VERSION 5.7 ;
BUSBITCHARS "[]" ;
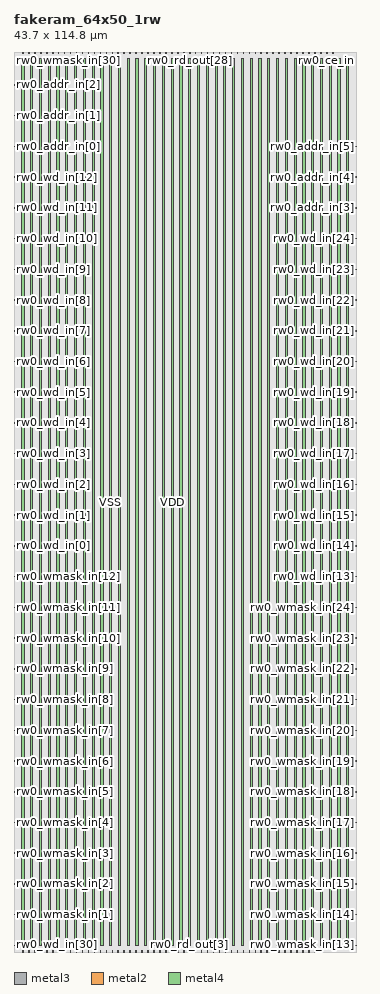
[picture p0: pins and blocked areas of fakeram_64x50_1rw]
MACRO fakeram_64x50_1rw
  FOREIGN fakeram_64x50_1rw 0 0 ;
  SYMMETRY X Y R90 ;
  SIZE 43.700 BY 114.800 ;
  CLASS BLOCK ;
  PIN rw0_wmask_in[0]
    DIRECTION INPUT ;
    USE SIGNAL ;
    SHAPE ABUTMENT ;
    PORT
      LAYER metal3 ;
      RECT 0.000 0.805 0.210 0.875 ;
    END
  END rw0_wmask_in[0]
  PIN rw0_wmask_in[1]
    DIRECTION INPUT ;
    USE SIGNAL ;
    SHAPE ABUTMENT ;
    PORT
      LAYER metal3 ;
      RECT 0.000 4.725 0.210 4.795 ;
    END
  END rw0_wmask_in[1]
  PIN rw0_wmask_in[2]
    DIRECTION INPUT ;
    USE SIGNAL ;
    SHAPE ABUTMENT ;
    PORT
      LAYER metal3 ;
      RECT 0.000 8.645 0.210 8.715 ;
    END
  END rw0_wmask_in[2]
  PIN rw0_wmask_in[3]
    DIRECTION INPUT ;
    USE SIGNAL ;
    SHAPE ABUTMENT ;
    PORT
      LAYER metal3 ;
      RECT 0.000 12.565 0.210 12.635 ;
    END
  END rw0_wmask_in[3]
  PIN rw0_wmask_in[4]
    DIRECTION INPUT ;
    USE SIGNAL ;
    SHAPE ABUTMENT ;
    PORT
      LAYER metal3 ;
      RECT 0.000 16.485 0.210 16.555 ;
    END
  END rw0_wmask_in[4]
  PIN rw0_wmask_in[5]
    DIRECTION INPUT ;
    USE SIGNAL ;
    SHAPE ABUTMENT ;
    PORT
      LAYER metal3 ;
      RECT 0.000 20.405 0.210 20.475 ;
    END
  END rw0_wmask_in[5]
  PIN rw0_wmask_in[6]
    DIRECTION INPUT ;
    USE SIGNAL ;
    SHAPE ABUTMENT ;
    PORT
      LAYER metal3 ;
      RECT 0.000 24.325 0.210 24.395 ;
    END
  END rw0_wmask_in[6]
  PIN rw0_wmask_in[7]
    DIRECTION INPUT ;
    USE SIGNAL ;
    SHAPE ABUTMENT ;
    PORT
      LAYER metal3 ;
      RECT 0.000 28.245 0.210 28.315 ;
    END
  END rw0_wmask_in[7]
  PIN rw0_wmask_in[8]
    DIRECTION INPUT ;
    USE SIGNAL ;
    SHAPE ABUTMENT ;
    PORT
      LAYER metal3 ;
      RECT 0.000 32.165 0.210 32.235 ;
    END
  END rw0_wmask_in[8]
  PIN rw0_wmask_in[9]
    DIRECTION INPUT ;
    USE SIGNAL ;
    SHAPE ABUTMENT ;
    PORT
      LAYER metal3 ;
      RECT 0.000 36.085 0.210 36.155 ;
    END
  END rw0_wmask_in[9]
  PIN rw0_wmask_in[10]
    DIRECTION INPUT ;
    USE SIGNAL ;
    SHAPE ABUTMENT ;
    PORT
      LAYER metal3 ;
      RECT 0.000 40.005 0.210 40.075 ;
    END
  END rw0_wmask_in[10]
  PIN rw0_wmask_in[11]
    DIRECTION INPUT ;
    USE SIGNAL ;
    SHAPE ABUTMENT ;
    PORT
      LAYER metal3 ;
      RECT 0.000 43.925 0.210 43.995 ;
    END
  END rw0_wmask_in[11]
  PIN rw0_wmask_in[12]
    DIRECTION INPUT ;
    USE SIGNAL ;
    SHAPE ABUTMENT ;
    PORT
      LAYER metal3 ;
      RECT 0.000 47.845 0.210 47.915 ;
    END
  END rw0_wmask_in[12]
  PIN rw0_wmask_in[13]
    DIRECTION INPUT ;
    USE SIGNAL ;
    SHAPE ABUTMENT ;
    PORT
      LAYER metal3 ;
      RECT 43.490 0.805 43.700 0.875 ;
    END
  END rw0_wmask_in[13]
  PIN rw0_wmask_in[14]
    DIRECTION INPUT ;
    USE SIGNAL ;
    SHAPE ABUTMENT ;
    PORT
      LAYER metal3 ;
      RECT 43.490 4.725 43.700 4.795 ;
    END
  END rw0_wmask_in[14]
  PIN rw0_wmask_in[15]
    DIRECTION INPUT ;
    USE SIGNAL ;
    SHAPE ABUTMENT ;
    PORT
      LAYER metal3 ;
      RECT 43.490 8.645 43.700 8.715 ;
    END
  END rw0_wmask_in[15]
  PIN rw0_wmask_in[16]
    DIRECTION INPUT ;
    USE SIGNAL ;
    SHAPE ABUTMENT ;
    PORT
      LAYER metal3 ;
      RECT 43.490 12.565 43.700 12.635 ;
    END
  END rw0_wmask_in[16]
  PIN rw0_wmask_in[17]
    DIRECTION INPUT ;
    USE SIGNAL ;
    SHAPE ABUTMENT ;
    PORT
      LAYER metal3 ;
      RECT 43.490 16.485 43.700 16.555 ;
    END
  END rw0_wmask_in[17]
  PIN rw0_wmask_in[18]
    DIRECTION INPUT ;
    USE SIGNAL ;
    SHAPE ABUTMENT ;
    PORT
      LAYER metal3 ;
      RECT 43.490 20.405 43.700 20.475 ;
    END
  END rw0_wmask_in[18]
  PIN rw0_wmask_in[19]
    DIRECTION INPUT ;
    USE SIGNAL ;
    SHAPE ABUTMENT ;
    PORT
      LAYER metal3 ;
      RECT 43.490 24.325 43.700 24.395 ;
    END
  END rw0_wmask_in[19]
  PIN rw0_wmask_in[20]
    DIRECTION INPUT ;
    USE SIGNAL ;
    SHAPE ABUTMENT ;
    PORT
      LAYER metal3 ;
      RECT 43.490 28.245 43.700 28.315 ;
    END
  END rw0_wmask_in[20]
  PIN rw0_wmask_in[21]
    DIRECTION INPUT ;
    USE SIGNAL ;
    SHAPE ABUTMENT ;
    PORT
      LAYER metal3 ;
      RECT 43.490 32.165 43.700 32.235 ;
    END
  END rw0_wmask_in[21]
  PIN rw0_wmask_in[22]
    DIRECTION INPUT ;
    USE SIGNAL ;
    SHAPE ABUTMENT ;
    PORT
      LAYER metal3 ;
      RECT 43.490 36.085 43.700 36.155 ;
    END
  END rw0_wmask_in[22]
  PIN rw0_wmask_in[23]
    DIRECTION INPUT ;
    USE SIGNAL ;
    SHAPE ABUTMENT ;
    PORT
      LAYER metal3 ;
      RECT 43.490 40.005 43.700 40.075 ;
    END
  END rw0_wmask_in[23]
  PIN rw0_wmask_in[24]
    DIRECTION INPUT ;
    USE SIGNAL ;
    SHAPE ABUTMENT ;
    PORT
      LAYER metal3 ;
      RECT 43.490 43.925 43.700 43.995 ;
    END
  END rw0_wmask_in[24]
  PIN rw0_wmask_in[25]
    DIRECTION INPUT ;
    USE SIGNAL ;
    SHAPE ABUTMENT ;
    PORT
      LAYER metal2 ;
      RECT 1.105 114.590 1.175 114.800 ;
    END
  END rw0_wmask_in[25]
  PIN rw0_wmask_in[26]
    DIRECTION INPUT ;
    USE SIGNAL ;
    SHAPE ABUTMENT ;
    PORT
      LAYER metal2 ;
      RECT 1.865 114.590 1.935 114.800 ;
    END
  END rw0_wmask_in[26]
  PIN rw0_wmask_in[27]
    DIRECTION INPUT ;
    USE SIGNAL ;
    SHAPE ABUTMENT ;
    PORT
      LAYER metal2 ;
      RECT 2.625 114.590 2.695 114.800 ;
    END
  END rw0_wmask_in[27]
  PIN rw0_wmask_in[28]
    DIRECTION INPUT ;
    USE SIGNAL ;
    SHAPE ABUTMENT ;
    PORT
      LAYER metal2 ;
      RECT 3.385 114.590 3.455 114.800 ;
    END
  END rw0_wmask_in[28]
  PIN rw0_wmask_in[29]
    DIRECTION INPUT ;
    USE SIGNAL ;
    SHAPE ABUTMENT ;
    PORT
      LAYER metal2 ;
      RECT 4.145 114.590 4.215 114.800 ;
    END
  END rw0_wmask_in[29]
  PIN rw0_wmask_in[30]
    DIRECTION INPUT ;
    USE SIGNAL ;
    SHAPE ABUTMENT ;
    PORT
      LAYER metal2 ;
      RECT 4.905 114.590 4.975 114.800 ;
    END
  END rw0_wmask_in[30]
  PIN rw0_wmask_in[31]
    DIRECTION INPUT ;
    USE SIGNAL ;
    SHAPE ABUTMENT ;
    PORT
      LAYER metal2 ;
      RECT 5.665 114.590 5.735 114.800 ;
    END
  END rw0_wmask_in[31]
  PIN rw0_wmask_in[32]
    DIRECTION INPUT ;
    USE SIGNAL ;
    SHAPE ABUTMENT ;
    PORT
      LAYER metal2 ;
      RECT 6.425 114.590 6.495 114.800 ;
    END
  END rw0_wmask_in[32]
  PIN rw0_wmask_in[33]
    DIRECTION INPUT ;
    USE SIGNAL ;
    SHAPE ABUTMENT ;
    PORT
      LAYER metal2 ;
      RECT 7.185 114.590 7.255 114.800 ;
    END
  END rw0_wmask_in[33]
  PIN rw0_wmask_in[34]
    DIRECTION INPUT ;
    USE SIGNAL ;
    SHAPE ABUTMENT ;
    PORT
      LAYER metal2 ;
      RECT 7.945 114.590 8.015 114.800 ;
    END
  END rw0_wmask_in[34]
  PIN rw0_wmask_in[35]
    DIRECTION INPUT ;
    USE SIGNAL ;
    SHAPE ABUTMENT ;
    PORT
      LAYER metal2 ;
      RECT 8.705 114.590 8.775 114.800 ;
    END
  END rw0_wmask_in[35]
  PIN rw0_wmask_in[36]
    DIRECTION INPUT ;
    USE SIGNAL ;
    SHAPE ABUTMENT ;
    PORT
      LAYER metal2 ;
      RECT 9.465 114.590 9.535 114.800 ;
    END
  END rw0_wmask_in[36]
  PIN rw0_wmask_in[37]
    DIRECTION INPUT ;
    USE SIGNAL ;
    SHAPE ABUTMENT ;
    PORT
      LAYER metal2 ;
      RECT 10.225 114.590 10.295 114.800 ;
    END
  END rw0_wmask_in[37]
  PIN rw0_wmask_in[38]
    DIRECTION INPUT ;
    USE SIGNAL ;
    SHAPE ABUTMENT ;
    PORT
      LAYER metal2 ;
      RECT 10.985 114.590 11.055 114.800 ;
    END
  END rw0_wmask_in[38]
  PIN rw0_wmask_in[39]
    DIRECTION INPUT ;
    USE SIGNAL ;
    SHAPE ABUTMENT ;
    PORT
      LAYER metal2 ;
      RECT 11.745 114.590 11.815 114.800 ;
    END
  END rw0_wmask_in[39]
  PIN rw0_wmask_in[40]
    DIRECTION INPUT ;
    USE SIGNAL ;
    SHAPE ABUTMENT ;
    PORT
      LAYER metal2 ;
      RECT 12.505 114.590 12.575 114.800 ;
    END
  END rw0_wmask_in[40]
  PIN rw0_wmask_in[41]
    DIRECTION INPUT ;
    USE SIGNAL ;
    SHAPE ABUTMENT ;
    PORT
      LAYER metal2 ;
      RECT 13.265 114.590 13.335 114.800 ;
    END
  END rw0_wmask_in[41]
  PIN rw0_wmask_in[42]
    DIRECTION INPUT ;
    USE SIGNAL ;
    SHAPE ABUTMENT ;
    PORT
      LAYER metal2 ;
      RECT 14.025 114.590 14.095 114.800 ;
    END
  END rw0_wmask_in[42]
  PIN rw0_wmask_in[43]
    DIRECTION INPUT ;
    USE SIGNAL ;
    SHAPE ABUTMENT ;
    PORT
      LAYER metal2 ;
      RECT 14.785 114.590 14.855 114.800 ;
    END
  END rw0_wmask_in[43]
  PIN rw0_wmask_in[44]
    DIRECTION INPUT ;
    USE SIGNAL ;
    SHAPE ABUTMENT ;
    PORT
      LAYER metal2 ;
      RECT 15.545 114.590 15.615 114.800 ;
    END
  END rw0_wmask_in[44]
  PIN rw0_wmask_in[45]
    DIRECTION INPUT ;
    USE SIGNAL ;
    SHAPE ABUTMENT ;
    PORT
      LAYER metal2 ;
      RECT 16.305 114.590 16.375 114.800 ;
    END
  END rw0_wmask_in[45]
  PIN rw0_wmask_in[46]
    DIRECTION INPUT ;
    USE SIGNAL ;
    SHAPE ABUTMENT ;
    PORT
      LAYER metal2 ;
      RECT 17.065 114.590 17.135 114.800 ;
    END
  END rw0_wmask_in[46]
  PIN rw0_wmask_in[47]
    DIRECTION INPUT ;
    USE SIGNAL ;
    SHAPE ABUTMENT ;
    PORT
      LAYER metal2 ;
      RECT 17.825 114.590 17.895 114.800 ;
    END
  END rw0_wmask_in[47]
  PIN rw0_wmask_in[48]
    DIRECTION INPUT ;
    USE SIGNAL ;
    SHAPE ABUTMENT ;
    PORT
      LAYER metal2 ;
      RECT 18.585 114.590 18.655 114.800 ;
    END
  END rw0_wmask_in[48]
  PIN rw0_wmask_in[49]
    DIRECTION INPUT ;
    USE SIGNAL ;
    SHAPE ABUTMENT ;
    PORT
      LAYER metal2 ;
      RECT 19.345 114.590 19.415 114.800 ;
    END
  END rw0_wmask_in[49]
  PIN rw0_wd_in[0]
    DIRECTION INPUT ;
    USE SIGNAL ;
    SHAPE ABUTMENT ;
    PORT
      LAYER metal3 ;
      RECT 0.000 51.765 0.210 51.835 ;
    END
  END rw0_wd_in[0]
  PIN rw0_wd_in[1]
    DIRECTION INPUT ;
    USE SIGNAL ;
    SHAPE ABUTMENT ;
    PORT
      LAYER metal3 ;
      RECT 0.000 55.685 0.210 55.755 ;
    END
  END rw0_wd_in[1]
  PIN rw0_wd_in[2]
    DIRECTION INPUT ;
    USE SIGNAL ;
    SHAPE ABUTMENT ;
    PORT
      LAYER metal3 ;
      RECT 0.000 59.605 0.210 59.675 ;
    END
  END rw0_wd_in[2]
  PIN rw0_wd_in[3]
    DIRECTION INPUT ;
    USE SIGNAL ;
    SHAPE ABUTMENT ;
    PORT
      LAYER metal3 ;
      RECT 0.000 63.525 0.210 63.595 ;
    END
  END rw0_wd_in[3]
  PIN rw0_wd_in[4]
    DIRECTION INPUT ;
    USE SIGNAL ;
    SHAPE ABUTMENT ;
    PORT
      LAYER metal3 ;
      RECT 0.000 67.445 0.210 67.515 ;
    END
  END rw0_wd_in[4]
  PIN rw0_wd_in[5]
    DIRECTION INPUT ;
    USE SIGNAL ;
    SHAPE ABUTMENT ;
    PORT
      LAYER metal3 ;
      RECT 0.000 71.365 0.210 71.435 ;
    END
  END rw0_wd_in[5]
  PIN rw0_wd_in[6]
    DIRECTION INPUT ;
    USE SIGNAL ;
    SHAPE ABUTMENT ;
    PORT
      LAYER metal3 ;
      RECT 0.000 75.285 0.210 75.355 ;
    END
  END rw0_wd_in[6]
  PIN rw0_wd_in[7]
    DIRECTION INPUT ;
    USE SIGNAL ;
    SHAPE ABUTMENT ;
    PORT
      LAYER metal3 ;
      RECT 0.000 79.205 0.210 79.275 ;
    END
  END rw0_wd_in[7]
  PIN rw0_wd_in[8]
    DIRECTION INPUT ;
    USE SIGNAL ;
    SHAPE ABUTMENT ;
    PORT
      LAYER metal3 ;
      RECT 0.000 83.125 0.210 83.195 ;
    END
  END rw0_wd_in[8]
  PIN rw0_wd_in[9]
    DIRECTION INPUT ;
    USE SIGNAL ;
    SHAPE ABUTMENT ;
    PORT
      LAYER metal3 ;
      RECT 0.000 87.045 0.210 87.115 ;
    END
  END rw0_wd_in[9]
  PIN rw0_wd_in[10]
    DIRECTION INPUT ;
    USE SIGNAL ;
    SHAPE ABUTMENT ;
    PORT
      LAYER metal3 ;
      RECT 0.000 90.965 0.210 91.035 ;
    END
  END rw0_wd_in[10]
  PIN rw0_wd_in[11]
    DIRECTION INPUT ;
    USE SIGNAL ;
    SHAPE ABUTMENT ;
    PORT
      LAYER metal3 ;
      RECT 0.000 94.885 0.210 94.955 ;
    END
  END rw0_wd_in[11]
  PIN rw0_wd_in[12]
    DIRECTION INPUT ;
    USE SIGNAL ;
    SHAPE ABUTMENT ;
    PORT
      LAYER metal3 ;
      RECT 0.000 98.805 0.210 98.875 ;
    END
  END rw0_wd_in[12]
  PIN rw0_wd_in[13]
    DIRECTION INPUT ;
    USE SIGNAL ;
    SHAPE ABUTMENT ;
    PORT
      LAYER metal3 ;
      RECT 43.490 47.845 43.700 47.915 ;
    END
  END rw0_wd_in[13]
  PIN rw0_wd_in[14]
    DIRECTION INPUT ;
    USE SIGNAL ;
    SHAPE ABUTMENT ;
    PORT
      LAYER metal3 ;
      RECT 43.490 51.765 43.700 51.835 ;
    END
  END rw0_wd_in[14]
  PIN rw0_wd_in[15]
    DIRECTION INPUT ;
    USE SIGNAL ;
    SHAPE ABUTMENT ;
    PORT
      LAYER metal3 ;
      RECT 43.490 55.685 43.700 55.755 ;
    END
  END rw0_wd_in[15]
  PIN rw0_wd_in[16]
    DIRECTION INPUT ;
    USE SIGNAL ;
    SHAPE ABUTMENT ;
    PORT
      LAYER metal3 ;
      RECT 43.490 59.605 43.700 59.675 ;
    END
  END rw0_wd_in[16]
  PIN rw0_wd_in[17]
    DIRECTION INPUT ;
    USE SIGNAL ;
    SHAPE ABUTMENT ;
    PORT
      LAYER metal3 ;
      RECT 43.490 63.525 43.700 63.595 ;
    END
  END rw0_wd_in[17]
  PIN rw0_wd_in[18]
    DIRECTION INPUT ;
    USE SIGNAL ;
    SHAPE ABUTMENT ;
    PORT
      LAYER metal3 ;
      RECT 43.490 67.445 43.700 67.515 ;
    END
  END rw0_wd_in[18]
  PIN rw0_wd_in[19]
    DIRECTION INPUT ;
    USE SIGNAL ;
    SHAPE ABUTMENT ;
    PORT
      LAYER metal3 ;
      RECT 43.490 71.365 43.700 71.435 ;
    END
  END rw0_wd_in[19]
  PIN rw0_wd_in[20]
    DIRECTION INPUT ;
    USE SIGNAL ;
    SHAPE ABUTMENT ;
    PORT
      LAYER metal3 ;
      RECT 43.490 75.285 43.700 75.355 ;
    END
  END rw0_wd_in[20]
  PIN rw0_wd_in[21]
    DIRECTION INPUT ;
    USE SIGNAL ;
    SHAPE ABUTMENT ;
    PORT
      LAYER metal3 ;
      RECT 43.490 79.205 43.700 79.275 ;
    END
  END rw0_wd_in[21]
  PIN rw0_wd_in[22]
    DIRECTION INPUT ;
    USE SIGNAL ;
    SHAPE ABUTMENT ;
    PORT
      LAYER metal3 ;
      RECT 43.490 83.125 43.700 83.195 ;
    END
  END rw0_wd_in[22]
  PIN rw0_wd_in[23]
    DIRECTION INPUT ;
    USE SIGNAL ;
    SHAPE ABUTMENT ;
    PORT
      LAYER metal3 ;
      RECT 43.490 87.045 43.700 87.115 ;
    END
  END rw0_wd_in[23]
  PIN rw0_wd_in[24]
    DIRECTION INPUT ;
    USE SIGNAL ;
    SHAPE ABUTMENT ;
    PORT
      LAYER metal3 ;
      RECT 43.490 90.965 43.700 91.035 ;
    END
  END rw0_wd_in[24]
  PIN rw0_wd_in[25]
    DIRECTION INPUT ;
    USE SIGNAL ;
    SHAPE ABUTMENT ;
    PORT
      LAYER metal2 ;
      RECT 1.105 0.000 1.175 0.210 ;
    END
  END rw0_wd_in[25]
  PIN rw0_wd_in[26]
    DIRECTION INPUT ;
    USE SIGNAL ;
    SHAPE ABUTMENT ;
    PORT
      LAYER metal2 ;
      RECT 1.865 0.000 1.935 0.210 ;
    END
  END rw0_wd_in[26]
  PIN rw0_wd_in[27]
    DIRECTION INPUT ;
    USE SIGNAL ;
    SHAPE ABUTMENT ;
    PORT
      LAYER metal2 ;
      RECT 2.625 0.000 2.695 0.210 ;
    END
  END rw0_wd_in[27]
  PIN rw0_wd_in[28]
    DIRECTION INPUT ;
    USE SIGNAL ;
    SHAPE ABUTMENT ;
    PORT
      LAYER metal2 ;
      RECT 3.385 0.000 3.455 0.210 ;
    END
  END rw0_wd_in[28]
  PIN rw0_wd_in[29]
    DIRECTION INPUT ;
    USE SIGNAL ;
    SHAPE ABUTMENT ;
    PORT
      LAYER metal2 ;
      RECT 4.145 0.000 4.215 0.210 ;
    END
  END rw0_wd_in[29]
  PIN rw0_wd_in[30]
    DIRECTION INPUT ;
    USE SIGNAL ;
    SHAPE ABUTMENT ;
    PORT
      LAYER metal2 ;
      RECT 4.905 0.000 4.975 0.210 ;
    END
  END rw0_wd_in[30]
  PIN rw0_wd_in[31]
    DIRECTION INPUT ;
    USE SIGNAL ;
    SHAPE ABUTMENT ;
    PORT
      LAYER metal2 ;
      RECT 5.665 0.000 5.735 0.210 ;
    END
  END rw0_wd_in[31]
  PIN rw0_wd_in[32]
    DIRECTION INPUT ;
    USE SIGNAL ;
    SHAPE ABUTMENT ;
    PORT
      LAYER metal2 ;
      RECT 6.425 0.000 6.495 0.210 ;
    END
  END rw0_wd_in[32]
  PIN rw0_wd_in[33]
    DIRECTION INPUT ;
    USE SIGNAL ;
    SHAPE ABUTMENT ;
    PORT
      LAYER metal2 ;
      RECT 7.185 0.000 7.255 0.210 ;
    END
  END rw0_wd_in[33]
  PIN rw0_wd_in[34]
    DIRECTION INPUT ;
    USE SIGNAL ;
    SHAPE ABUTMENT ;
    PORT
      LAYER metal2 ;
      RECT 7.945 0.000 8.015 0.210 ;
    END
  END rw0_wd_in[34]
  PIN rw0_wd_in[35]
    DIRECTION INPUT ;
    USE SIGNAL ;
    SHAPE ABUTMENT ;
    PORT
      LAYER metal2 ;
      RECT 8.705 0.000 8.775 0.210 ;
    END
  END rw0_wd_in[35]
  PIN rw0_wd_in[36]
    DIRECTION INPUT ;
    USE SIGNAL ;
    SHAPE ABUTMENT ;
    PORT
      LAYER metal2 ;
      RECT 9.465 0.000 9.535 0.210 ;
    END
  END rw0_wd_in[36]
  PIN rw0_wd_in[37]
    DIRECTION INPUT ;
    USE SIGNAL ;
    SHAPE ABUTMENT ;
    PORT
      LAYER metal2 ;
      RECT 10.225 0.000 10.295 0.210 ;
    END
  END rw0_wd_in[37]
  PIN rw0_wd_in[38]
    DIRECTION INPUT ;
    USE SIGNAL ;
    SHAPE ABUTMENT ;
    PORT
      LAYER metal2 ;
      RECT 10.985 0.000 11.055 0.210 ;
    END
  END rw0_wd_in[38]
  PIN rw0_wd_in[39]
    DIRECTION INPUT ;
    USE SIGNAL ;
    SHAPE ABUTMENT ;
    PORT
      LAYER metal2 ;
      RECT 11.745 0.000 11.815 0.210 ;
    END
  END rw0_wd_in[39]
  PIN rw0_wd_in[40]
    DIRECTION INPUT ;
    USE SIGNAL ;
    SHAPE ABUTMENT ;
    PORT
      LAYER metal2 ;
      RECT 12.505 0.000 12.575 0.210 ;
    END
  END rw0_wd_in[40]
  PIN rw0_wd_in[41]
    DIRECTION INPUT ;
    USE SIGNAL ;
    SHAPE ABUTMENT ;
    PORT
      LAYER metal2 ;
      RECT 13.265 0.000 13.335 0.210 ;
    END
  END rw0_wd_in[41]
  PIN rw0_wd_in[42]
    DIRECTION INPUT ;
    USE SIGNAL ;
    SHAPE ABUTMENT ;
    PORT
      LAYER metal2 ;
      RECT 14.025 0.000 14.095 0.210 ;
    END
  END rw0_wd_in[42]
  PIN rw0_wd_in[43]
    DIRECTION INPUT ;
    USE SIGNAL ;
    SHAPE ABUTMENT ;
    PORT
      LAYER metal2 ;
      RECT 14.785 0.000 14.855 0.210 ;
    END
  END rw0_wd_in[43]
  PIN rw0_wd_in[44]
    DIRECTION INPUT ;
    USE SIGNAL ;
    SHAPE ABUTMENT ;
    PORT
      LAYER metal2 ;
      RECT 15.545 0.000 15.615 0.210 ;
    END
  END rw0_wd_in[44]
  PIN rw0_wd_in[45]
    DIRECTION INPUT ;
    USE SIGNAL ;
    SHAPE ABUTMENT ;
    PORT
      LAYER metal2 ;
      RECT 16.305 0.000 16.375 0.210 ;
    END
  END rw0_wd_in[45]
  PIN rw0_wd_in[46]
    DIRECTION INPUT ;
    USE SIGNAL ;
    SHAPE ABUTMENT ;
    PORT
      LAYER metal2 ;
      RECT 17.065 0.000 17.135 0.210 ;
    END
  END rw0_wd_in[46]
  PIN rw0_wd_in[47]
    DIRECTION INPUT ;
    USE SIGNAL ;
    SHAPE ABUTMENT ;
    PORT
      LAYER metal2 ;
      RECT 17.825 0.000 17.895 0.210 ;
    END
  END rw0_wd_in[47]
  PIN rw0_wd_in[48]
    DIRECTION INPUT ;
    USE SIGNAL ;
    SHAPE ABUTMENT ;
    PORT
      LAYER metal2 ;
      RECT 18.585 0.000 18.655 0.210 ;
    END
  END rw0_wd_in[48]
  PIN rw0_wd_in[49]
    DIRECTION INPUT ;
    USE SIGNAL ;
    SHAPE ABUTMENT ;
    PORT
      LAYER metal2 ;
      RECT 19.345 0.000 19.415 0.210 ;
    END
  END rw0_wd_in[49]
  PIN rw0_rd_out[0]
    DIRECTION OUTPUT ;
    USE SIGNAL ;
    SHAPE ABUTMENT ;
    PORT
      LAYER metal2 ;
      RECT 20.105 0.000 20.175 0.210 ;
    END
  END rw0_rd_out[0]
  PIN rw0_rd_out[1]
    DIRECTION OUTPUT ;
    USE SIGNAL ;
    SHAPE ABUTMENT ;
    PORT
      LAYER metal2 ;
      RECT 20.865 0.000 20.935 0.210 ;
    END
  END rw0_rd_out[1]
  PIN rw0_rd_out[2]
    DIRECTION OUTPUT ;
    USE SIGNAL ;
    SHAPE ABUTMENT ;
    PORT
      LAYER metal2 ;
      RECT 21.625 0.000 21.695 0.210 ;
    END
  END rw0_rd_out[2]
  PIN rw0_rd_out[3]
    DIRECTION OUTPUT ;
    USE SIGNAL ;
    SHAPE ABUTMENT ;
    PORT
      LAYER metal2 ;
      RECT 22.385 0.000 22.455 0.210 ;
    END
  END rw0_rd_out[3]
  PIN rw0_rd_out[4]
    DIRECTION OUTPUT ;
    USE SIGNAL ;
    SHAPE ABUTMENT ;
    PORT
      LAYER metal2 ;
      RECT 23.145 0.000 23.215 0.210 ;
    END
  END rw0_rd_out[4]
  PIN rw0_rd_out[5]
    DIRECTION OUTPUT ;
    USE SIGNAL ;
    SHAPE ABUTMENT ;
    PORT
      LAYER metal2 ;
      RECT 23.905 0.000 23.975 0.210 ;
    END
  END rw0_rd_out[5]
  PIN rw0_rd_out[6]
    DIRECTION OUTPUT ;
    USE SIGNAL ;
    SHAPE ABUTMENT ;
    PORT
      LAYER metal2 ;
      RECT 24.665 0.000 24.735 0.210 ;
    END
  END rw0_rd_out[6]
  PIN rw0_rd_out[7]
    DIRECTION OUTPUT ;
    USE SIGNAL ;
    SHAPE ABUTMENT ;
    PORT
      LAYER metal2 ;
      RECT 25.425 0.000 25.495 0.210 ;
    END
  END rw0_rd_out[7]
  PIN rw0_rd_out[8]
    DIRECTION OUTPUT ;
    USE SIGNAL ;
    SHAPE ABUTMENT ;
    PORT
      LAYER metal2 ;
      RECT 26.185 0.000 26.255 0.210 ;
    END
  END rw0_rd_out[8]
  PIN rw0_rd_out[9]
    DIRECTION OUTPUT ;
    USE SIGNAL ;
    SHAPE ABUTMENT ;
    PORT
      LAYER metal2 ;
      RECT 26.945 0.000 27.015 0.210 ;
    END
  END rw0_rd_out[9]
  PIN rw0_rd_out[10]
    DIRECTION OUTPUT ;
    USE SIGNAL ;
    SHAPE ABUTMENT ;
    PORT
      LAYER metal2 ;
      RECT 27.705 0.000 27.775 0.210 ;
    END
  END rw0_rd_out[10]
  PIN rw0_rd_out[11]
    DIRECTION OUTPUT ;
    USE SIGNAL ;
    SHAPE ABUTMENT ;
    PORT
      LAYER metal2 ;
      RECT 28.465 0.000 28.535 0.210 ;
    END
  END rw0_rd_out[11]
  PIN rw0_rd_out[12]
    DIRECTION OUTPUT ;
    USE SIGNAL ;
    SHAPE ABUTMENT ;
    PORT
      LAYER metal2 ;
      RECT 29.225 0.000 29.295 0.210 ;
    END
  END rw0_rd_out[12]
  PIN rw0_rd_out[13]
    DIRECTION OUTPUT ;
    USE SIGNAL ;
    SHAPE ABUTMENT ;
    PORT
      LAYER metal2 ;
      RECT 29.985 0.000 30.055 0.210 ;
    END
  END rw0_rd_out[13]
  PIN rw0_rd_out[14]
    DIRECTION OUTPUT ;
    USE SIGNAL ;
    SHAPE ABUTMENT ;
    PORT
      LAYER metal2 ;
      RECT 30.745 0.000 30.815 0.210 ;
    END
  END rw0_rd_out[14]
  PIN rw0_rd_out[15]
    DIRECTION OUTPUT ;
    USE SIGNAL ;
    SHAPE ABUTMENT ;
    PORT
      LAYER metal2 ;
      RECT 31.505 0.000 31.575 0.210 ;
    END
  END rw0_rd_out[15]
  PIN rw0_rd_out[16]
    DIRECTION OUTPUT ;
    USE SIGNAL ;
    SHAPE ABUTMENT ;
    PORT
      LAYER metal2 ;
      RECT 32.265 0.000 32.335 0.210 ;
    END
  END rw0_rd_out[16]
  PIN rw0_rd_out[17]
    DIRECTION OUTPUT ;
    USE SIGNAL ;
    SHAPE ABUTMENT ;
    PORT
      LAYER metal2 ;
      RECT 33.025 0.000 33.095 0.210 ;
    END
  END rw0_rd_out[17]
  PIN rw0_rd_out[18]
    DIRECTION OUTPUT ;
    USE SIGNAL ;
    SHAPE ABUTMENT ;
    PORT
      LAYER metal2 ;
      RECT 33.785 0.000 33.855 0.210 ;
    END
  END rw0_rd_out[18]
  PIN rw0_rd_out[19]
    DIRECTION OUTPUT ;
    USE SIGNAL ;
    SHAPE ABUTMENT ;
    PORT
      LAYER metal2 ;
      RECT 34.545 0.000 34.615 0.210 ;
    END
  END rw0_rd_out[19]
  PIN rw0_rd_out[20]
    DIRECTION OUTPUT ;
    USE SIGNAL ;
    SHAPE ABUTMENT ;
    PORT
      LAYER metal2 ;
      RECT 35.305 0.000 35.375 0.210 ;
    END
  END rw0_rd_out[20]
  PIN rw0_rd_out[21]
    DIRECTION OUTPUT ;
    USE SIGNAL ;
    SHAPE ABUTMENT ;
    PORT
      LAYER metal2 ;
      RECT 36.065 0.000 36.135 0.210 ;
    END
  END rw0_rd_out[21]
  PIN rw0_rd_out[22]
    DIRECTION OUTPUT ;
    USE SIGNAL ;
    SHAPE ABUTMENT ;
    PORT
      LAYER metal2 ;
      RECT 36.825 0.000 36.895 0.210 ;
    END
  END rw0_rd_out[22]
  PIN rw0_rd_out[23]
    DIRECTION OUTPUT ;
    USE SIGNAL ;
    SHAPE ABUTMENT ;
    PORT
      LAYER metal2 ;
      RECT 37.585 0.000 37.655 0.210 ;
    END
  END rw0_rd_out[23]
  PIN rw0_rd_out[24]
    DIRECTION OUTPUT ;
    USE SIGNAL ;
    SHAPE ABUTMENT ;
    PORT
      LAYER metal2 ;
      RECT 38.345 0.000 38.415 0.210 ;
    END
  END rw0_rd_out[24]
  PIN rw0_rd_out[25]
    DIRECTION OUTPUT ;
    USE SIGNAL ;
    SHAPE ABUTMENT ;
    PORT
      LAYER metal2 ;
      RECT 20.105 114.590 20.175 114.800 ;
    END
  END rw0_rd_out[25]
  PIN rw0_rd_out[26]
    DIRECTION OUTPUT ;
    USE SIGNAL ;
    SHAPE ABUTMENT ;
    PORT
      LAYER metal2 ;
      RECT 20.865 114.590 20.935 114.800 ;
    END
  END rw0_rd_out[26]
  PIN rw0_rd_out[27]
    DIRECTION OUTPUT ;
    USE SIGNAL ;
    SHAPE ABUTMENT ;
    PORT
      LAYER metal2 ;
      RECT 21.625 114.590 21.695 114.800 ;
    END
  END rw0_rd_out[27]
  PIN rw0_rd_out[28]
    DIRECTION OUTPUT ;
    USE SIGNAL ;
    SHAPE ABUTMENT ;
    PORT
      LAYER metal2 ;
      RECT 22.385 114.590 22.455 114.800 ;
    END
  END rw0_rd_out[28]
  PIN rw0_rd_out[29]
    DIRECTION OUTPUT ;
    USE SIGNAL ;
    SHAPE ABUTMENT ;
    PORT
      LAYER metal2 ;
      RECT 23.145 114.590 23.215 114.800 ;
    END
  END rw0_rd_out[29]
  PIN rw0_rd_out[30]
    DIRECTION OUTPUT ;
    USE SIGNAL ;
    SHAPE ABUTMENT ;
    PORT
      LAYER metal2 ;
      RECT 23.905 114.590 23.975 114.800 ;
    END
  END rw0_rd_out[30]
  PIN rw0_rd_out[31]
    DIRECTION OUTPUT ;
    USE SIGNAL ;
    SHAPE ABUTMENT ;
    PORT
      LAYER metal2 ;
      RECT 24.665 114.590 24.735 114.800 ;
    END
  END rw0_rd_out[31]
  PIN rw0_rd_out[32]
    DIRECTION OUTPUT ;
    USE SIGNAL ;
    SHAPE ABUTMENT ;
    PORT
      LAYER metal2 ;
      RECT 25.425 114.590 25.495 114.800 ;
    END
  END rw0_rd_out[32]
  PIN rw0_rd_out[33]
    DIRECTION OUTPUT ;
    USE SIGNAL ;
    SHAPE ABUTMENT ;
    PORT
      LAYER metal2 ;
      RECT 26.185 114.590 26.255 114.800 ;
    END
  END rw0_rd_out[33]
  PIN rw0_rd_out[34]
    DIRECTION OUTPUT ;
    USE SIGNAL ;
    SHAPE ABUTMENT ;
    PORT
      LAYER metal2 ;
      RECT 26.945 114.590 27.015 114.800 ;
    END
  END rw0_rd_out[34]
  PIN rw0_rd_out[35]
    DIRECTION OUTPUT ;
    USE SIGNAL ;
    SHAPE ABUTMENT ;
    PORT
      LAYER metal2 ;
      RECT 27.705 114.590 27.775 114.800 ;
    END
  END rw0_rd_out[35]
  PIN rw0_rd_out[36]
    DIRECTION OUTPUT ;
    USE SIGNAL ;
    SHAPE ABUTMENT ;
    PORT
      LAYER metal2 ;
      RECT 28.465 114.590 28.535 114.800 ;
    END
  END rw0_rd_out[36]
  PIN rw0_rd_out[37]
    DIRECTION OUTPUT ;
    USE SIGNAL ;
    SHAPE ABUTMENT ;
    PORT
      LAYER metal2 ;
      RECT 29.225 114.590 29.295 114.800 ;
    END
  END rw0_rd_out[37]
  PIN rw0_rd_out[38]
    DIRECTION OUTPUT ;
    USE SIGNAL ;
    SHAPE ABUTMENT ;
    PORT
      LAYER metal2 ;
      RECT 29.985 114.590 30.055 114.800 ;
    END
  END rw0_rd_out[38]
  PIN rw0_rd_out[39]
    DIRECTION OUTPUT ;
    USE SIGNAL ;
    SHAPE ABUTMENT ;
    PORT
      LAYER metal2 ;
      RECT 30.745 114.590 30.815 114.800 ;
    END
  END rw0_rd_out[39]
  PIN rw0_rd_out[40]
    DIRECTION OUTPUT ;
    USE SIGNAL ;
    SHAPE ABUTMENT ;
    PORT
      LAYER metal2 ;
      RECT 31.505 114.590 31.575 114.800 ;
    END
  END rw0_rd_out[40]
  PIN rw0_rd_out[41]
    DIRECTION OUTPUT ;
    USE SIGNAL ;
    SHAPE ABUTMENT ;
    PORT
      LAYER metal2 ;
      RECT 32.265 114.590 32.335 114.800 ;
    END
  END rw0_rd_out[41]
  PIN rw0_rd_out[42]
    DIRECTION OUTPUT ;
    USE SIGNAL ;
    SHAPE ABUTMENT ;
    PORT
      LAYER metal2 ;
      RECT 33.025 114.590 33.095 114.800 ;
    END
  END rw0_rd_out[42]
  PIN rw0_rd_out[43]
    DIRECTION OUTPUT ;
    USE SIGNAL ;
    SHAPE ABUTMENT ;
    PORT
      LAYER metal2 ;
      RECT 33.785 114.590 33.855 114.800 ;
    END
  END rw0_rd_out[43]
  PIN rw0_rd_out[44]
    DIRECTION OUTPUT ;
    USE SIGNAL ;
    SHAPE ABUTMENT ;
    PORT
      LAYER metal2 ;
      RECT 34.545 114.590 34.615 114.800 ;
    END
  END rw0_rd_out[44]
  PIN rw0_rd_out[45]
    DIRECTION OUTPUT ;
    USE SIGNAL ;
    SHAPE ABUTMENT ;
    PORT
      LAYER metal2 ;
      RECT 35.305 114.590 35.375 114.800 ;
    END
  END rw0_rd_out[45]
  PIN rw0_rd_out[46]
    DIRECTION OUTPUT ;
    USE SIGNAL ;
    SHAPE ABUTMENT ;
    PORT
      LAYER metal2 ;
      RECT 36.065 114.590 36.135 114.800 ;
    END
  END rw0_rd_out[46]
  PIN rw0_rd_out[47]
    DIRECTION OUTPUT ;
    USE SIGNAL ;
    SHAPE ABUTMENT ;
    PORT
      LAYER metal2 ;
      RECT 36.825 114.590 36.895 114.800 ;
    END
  END rw0_rd_out[47]
  PIN rw0_rd_out[48]
    DIRECTION OUTPUT ;
    USE SIGNAL ;
    SHAPE ABUTMENT ;
    PORT
      LAYER metal2 ;
      RECT 37.585 114.590 37.655 114.800 ;
    END
  END rw0_rd_out[48]
  PIN rw0_rd_out[49]
    DIRECTION OUTPUT ;
    USE SIGNAL ;
    SHAPE ABUTMENT ;
    PORT
      LAYER metal2 ;
      RECT 38.345 114.590 38.415 114.800 ;
    END
  END rw0_rd_out[49]
  PIN rw0_addr_in[0]
    DIRECTION INPUT ;
    USE SIGNAL ;
    SHAPE ABUTMENT ;
    PORT
      LAYER metal3 ;
      RECT 0.000 102.725 0.210 102.795 ;
    END
  END rw0_addr_in[0]
  PIN rw0_addr_in[1]
    DIRECTION INPUT ;
    USE SIGNAL ;
    SHAPE ABUTMENT ;
    PORT
      LAYER metal3 ;
      RECT 0.000 106.645 0.210 106.715 ;
    END
  END rw0_addr_in[1]
  PIN rw0_addr_in[2]
    DIRECTION INPUT ;
    USE SIGNAL ;
    SHAPE ABUTMENT ;
    PORT
      LAYER metal3 ;
      RECT 0.000 110.565 0.210 110.635 ;
    END
  END rw0_addr_in[2]
  PIN rw0_addr_in[3]
    DIRECTION INPUT ;
    USE SIGNAL ;
    SHAPE ABUTMENT ;
    PORT
      LAYER metal3 ;
      RECT 43.490 94.885 43.700 94.955 ;
    END
  END rw0_addr_in[3]
  PIN rw0_addr_in[4]
    DIRECTION INPUT ;
    USE SIGNAL ;
    SHAPE ABUTMENT ;
    PORT
      LAYER metal3 ;
      RECT 43.490 98.805 43.700 98.875 ;
    END
  END rw0_addr_in[4]
  PIN rw0_addr_in[5]
    DIRECTION INPUT ;
    USE SIGNAL ;
    SHAPE ABUTMENT ;
    PORT
      LAYER metal3 ;
      RECT 43.490 102.725 43.700 102.795 ;
    END
  END rw0_addr_in[5]
  PIN rw0_we_in
    DIRECTION INPUT ;
    USE SIGNAL ;
    SHAPE ABUTMENT ;
    PORT
      LAYER metal2 ;
      RECT 39.105 114.590 39.175 114.800 ;
    END
  END rw0_we_in
  PIN rw0_ce_in
    DIRECTION INPUT ;
    USE SIGNAL ;
    SHAPE ABUTMENT ;
    PORT
      LAYER metal2 ;
      RECT 39.865 114.590 39.935 114.800 ;
    END
  END rw0_ce_in
  PIN rw0_clk
    DIRECTION INPUT ;
    USE SIGNAL ;
    SHAPE ABUTMENT ;
    PORT
      LAYER metal2 ;
      RECT 40.625 114.590 40.695 114.800 ;
    END
  END rw0_clk
  PIN VSS
    DIRECTION INOUT ;
    USE GROUND ;
    PORT
      LAYER metal4 ;
      RECT 1.000 0.840 1.280 113.960 ;
      RECT 3.240 0.840 3.520 113.960 ;
      RECT 5.480 0.840 5.760 113.960 ;
      RECT 7.720 0.840 8.000 113.960 ;
      RECT 9.960 0.840 10.240 113.960 ;
      RECT 12.200 0.840 12.480 113.960 ;
      RECT 14.440 0.840 14.720 113.960 ;
      RECT 16.680 0.840 16.960 113.960 ;
      RECT 18.920 0.840 19.200 113.960 ;
      RECT 21.160 0.840 21.440 113.960 ;
      RECT 23.400 0.840 23.680 113.960 ;
      RECT 25.640 0.840 25.920 113.960 ;
      RECT 27.880 0.840 28.160 113.960 ;
      RECT 30.120 0.840 30.400 113.960 ;
      RECT 32.360 0.840 32.640 113.960 ;
      RECT 34.600 0.840 34.880 113.960 ;
      RECT 36.840 0.840 37.120 113.960 ;
      RECT 39.080 0.840 39.360 113.960 ;
      RECT 41.320 0.840 41.600 113.960 ;
    END
  END VSS
  PIN VDD
    DIRECTION INOUT ;
    USE POWER ;
    PORT
      LAYER metal4 ;
      RECT 2.120 0.840 2.400 113.960 ;
      RECT 4.360 0.840 4.640 113.960 ;
      RECT 6.600 0.840 6.880 113.960 ;
      RECT 8.840 0.840 9.120 113.960 ;
      RECT 11.080 0.840 11.360 113.960 ;
      RECT 13.320 0.840 13.600 113.960 ;
      RECT 15.560 0.840 15.840 113.960 ;
      RECT 17.800 0.840 18.080 113.960 ;
      RECT 20.040 0.840 20.320 113.960 ;
      RECT 22.280 0.840 22.560 113.960 ;
      RECT 24.520 0.840 24.800 113.960 ;
      RECT 26.760 0.840 27.040 113.960 ;
      RECT 29.000 0.840 29.280 113.960 ;
      RECT 31.240 0.840 31.520 113.960 ;
      RECT 33.480 0.840 33.760 113.960 ;
      RECT 35.720 0.840 36.000 113.960 ;
      RECT 37.960 0.840 38.240 113.960 ;
      RECT 40.200 0.840 40.480 113.960 ;
      RECT 42.440 0.840 42.720 113.960 ;
    END
  END VDD
  OBS
    LAYER metal1 ;
    RECT 0 0 43.700 114.800 ;
    LAYER metal2 ;
    RECT 0 0 43.700 114.800 ;
    LAYER metal3 ;
    RECT 0 0 43.700 114.800 ;
    LAYER metal4 ;
    RECT 0 0 43.700 114.800 ;
    LAYER OVERLAP ;
    RECT 0 0 43.700 114.800 ;
  END
END fakeram_64x50_1rw

END LIBRARY
